VERSION 5.4 ;
NAMESCASESENSITIVE ON ;
BUSBITCHARS "[]" ;
DIVIDERCHAR "/" ;
UNITS
  DATABASE MICRONS 2000 ;
END UNITS
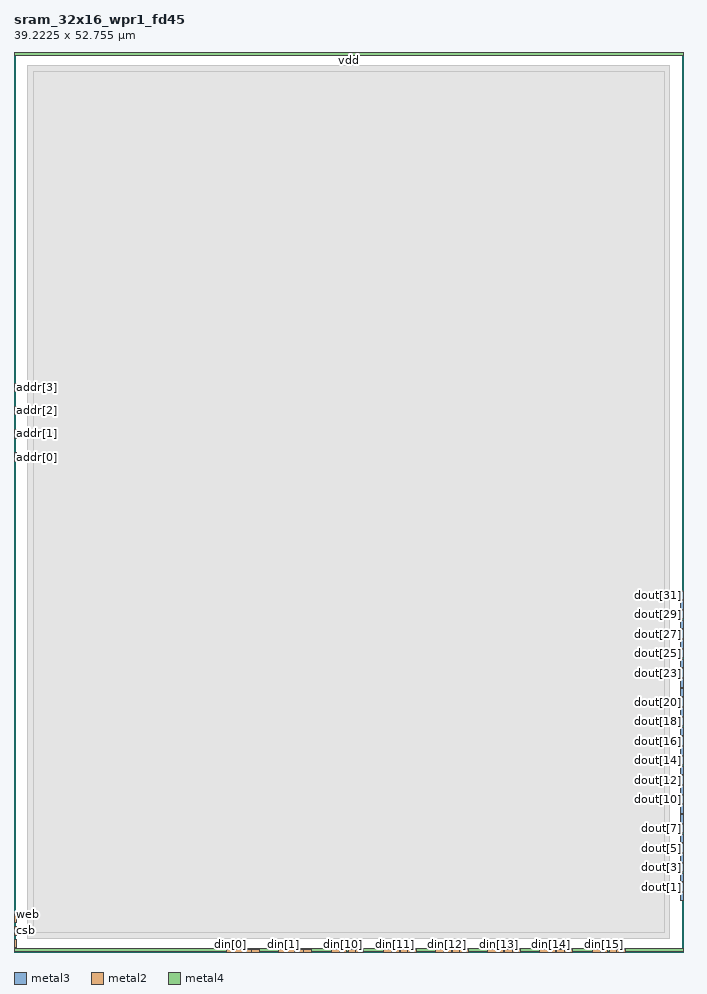
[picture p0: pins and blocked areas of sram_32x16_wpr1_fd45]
MACRO sram_32x16_wpr1_fd45
   CLASS BLOCK ;
   SIZE 39.2225 BY 52.7550 ;
   SYMMETRY X Y R90 ;
   PIN addr[0]
      DIRECTION INPUT ;
      PORT
         LAYER metal3 ;
         RECT 0.0000 28.7575 0.1600 29.2575 ;
      END
   END addr[0]
   PIN addr[1]
      DIRECTION INPUT ;
      PORT
         LAYER metal3 ;
         RECT 0.0000 30.1225 0.1600 30.6225 ;
      END
   END addr[1]
   PIN addr[2]
      DIRECTION INPUT ;
      PORT
         LAYER metal3 ;
         RECT 0.0000 31.4875 0.1600 31.9875 ;
      END
   END addr[2]
   PIN addr[3]
      DIRECTION INPUT ;
      PORT
         LAYER metal3 ;
         RECT 0.0000 32.8525 0.1600 33.3525 ;
      END
   END addr[3]
   PIN clk
      DIRECTION INPUT ;
      PORT
         LAYER metal2 ;
         RECT 0.0000 0.2425 0.1600 0.7425 ;
      END
   END clk
   PIN csb
      DIRECTION INPUT ;
      PORT
         LAYER metal2 ;
         RECT 0.0000 0.9925 0.1600 1.4925 ;
      END
   END csb
   PIN din[0]
      DIRECTION INPUT ;
      PORT
         LAYER metal2 ;
         RECT 12.4650 0.0000 12.9650 0.1600 ;
      END
   END din[0]
   PIN din[10]
      DIRECTION INPUT ;
      PORT
         LAYER metal2 ;
         RECT 19.0140 0.0000 19.5140 0.1600 ;
      END
   END din[10]
   PIN din[11]
      DIRECTION INPUT ;
      PORT
         LAYER metal2 ;
         RECT 22.0740 0.0000 22.5740 0.1600 ;
      END
   END din[11]
   PIN din[12]
      DIRECTION INPUT ;
      PORT
         LAYER metal2 ;
         RECT 25.1340 0.0000 25.6340 0.1600 ;
      END
   END din[12]
   PIN din[13]
      DIRECTION INPUT ;
      PORT
         LAYER metal2 ;
         RECT 28.1940 0.0000 28.6940 0.1600 ;
      END
   END din[13]
   PIN din[14]
      DIRECTION INPUT ;
      PORT
         LAYER metal2 ;
         RECT 31.2540 0.0000 31.7540 0.1600 ;
      END
   END din[14]
   PIN din[15]
      DIRECTION INPUT ;
      PORT
         LAYER metal2 ;
         RECT 34.3140 0.0000 34.8140 0.1600 ;
      END
   END din[15]
   PIN din[16]
      DIRECTION INPUT ;
      PORT
         LAYER metal2 ;
         RECT 13.4660 0.0000 13.9660 0.1600 ;
      END
   END din[16]
   PIN din[17]
      DIRECTION INPUT ;
      PORT
         LAYER metal2 ;
         RECT 16.5260 0.0000 17.0260 0.1600 ;
      END
   END din[17]
   PIN din[18]
      DIRECTION INPUT ;
      PORT
         LAYER metal2 ;
         RECT 19.5860 0.0000 20.0860 0.1600 ;
      END
   END din[18]
   PIN din[19]
      DIRECTION INPUT ;
      PORT
         LAYER metal2 ;
         RECT 22.6460 0.0000 23.1460 0.1600 ;
      END
   END din[19]
   PIN din[1]
      DIRECTION INPUT ;
      PORT
         LAYER metal2 ;
         RECT 15.5250 0.0000 16.0250 0.1600 ;
      END
   END din[1]
   PIN din[20]
      DIRECTION INPUT ;
      PORT
         LAYER metal2 ;
         RECT 25.7060 0.0000 26.2060 0.1600 ;
      END
   END din[20]
   PIN din[21]
      DIRECTION INPUT ;
      PORT
         LAYER metal2 ;
         RECT 28.7660 0.0000 29.2660 0.1600 ;
      END
   END din[21]
   PIN din[22]
      DIRECTION INPUT ;
      PORT
         LAYER metal2 ;
         RECT 31.8260 0.0000 32.3260 0.1600 ;
      END
   END din[22]
   PIN din[23]
      DIRECTION INPUT ;
      PORT
         LAYER metal2 ;
         RECT 34.8860 0.0000 35.3860 0.1600 ;
      END
   END din[23]
   PIN din[24]
      DIRECTION INPUT ;
      PORT
         LAYER metal2 ;
         RECT 13.8950 0.0000 14.3950 0.1600 ;
      END
   END din[24]
   PIN din[25]
      DIRECTION INPUT ;
      PORT
         LAYER metal2 ;
         RECT 16.9550 0.0000 17.4550 0.1600 ;
      END
   END din[25]
   PIN din[26]
      DIRECTION INPUT ;
      PORT
         LAYER metal2 ;
         RECT 20.0150 0.0000 20.5150 0.1600 ;
      END
   END din[26]
   PIN din[27]
      DIRECTION INPUT ;
      PORT
         LAYER metal2 ;
         RECT 23.0750 0.0000 23.5750 0.1600 ;
      END
   END din[27]
   PIN din[28]
      DIRECTION INPUT ;
      PORT
         LAYER metal2 ;
         RECT 26.1350 0.0000 26.6350 0.1600 ;
      END
   END din[28]
   PIN din[29]
      DIRECTION INPUT ;
      PORT
         LAYER metal2 ;
         RECT 29.1950 0.0000 29.6950 0.1600 ;
      END
   END din[29]
   PIN din[2]
      DIRECTION INPUT ;
      PORT
         LAYER metal2 ;
         RECT 18.5850 0.0000 19.0850 0.1600 ;
      END
   END din[2]
   PIN din[30]
      DIRECTION INPUT ;
      PORT
         LAYER metal2 ;
         RECT 32.2550 0.0000 32.7550 0.1600 ;
      END
   END din[30]
   PIN din[31]
      DIRECTION INPUT ;
      PORT
         LAYER metal2 ;
         RECT 35.3150 0.0000 35.8150 0.1600 ;
      END
   END din[31]
   PIN din[3]
      DIRECTION INPUT ;
      PORT
         LAYER metal2 ;
         RECT 21.6450 0.0000 22.1450 0.1600 ;
      END
   END din[3]
   PIN din[4]
      DIRECTION INPUT ;
      PORT
         LAYER metal2 ;
         RECT 24.7050 0.0000 25.2050 0.1600 ;
      END
   END din[4]
   PIN din[5]
      DIRECTION INPUT ;
      PORT
         LAYER metal2 ;
         RECT 27.7650 0.0000 28.2650 0.1600 ;
      END
   END din[5]
   PIN din[6]
      DIRECTION INPUT ;
      PORT
         LAYER metal2 ;
         RECT 30.8250 0.0000 31.3250 0.1600 ;
      END
   END din[6]
   PIN din[7]
      DIRECTION INPUT ;
      PORT
         LAYER metal2 ;
         RECT 33.8850 0.0000 34.3850 0.1600 ;
      END
   END din[7]
   PIN din[8]
      DIRECTION INPUT ;
      PORT
         LAYER metal2 ;
         RECT 12.8940 0.0000 13.3940 0.1600 ;
      END
   END din[8]
   PIN din[9]
      DIRECTION INPUT ;
      PORT
         LAYER metal2 ;
         RECT 15.9540 0.0000 16.4540 0.1600 ;
      END
   END din[9]
   PIN dout[0]
      DIRECTION OUTPUT ;
      PORT
         LAYER metal3 ;
         RECT 39.0625 2.9900 39.2225 3.4900 ;
      END
   END dout[0]
   PIN dout[10]
      DIRECTION OUTPUT ;
      PORT
         LAYER metal3 ;
         RECT 39.0625 8.6900 39.2225 9.1900 ;
      END
   END dout[10]
   PIN dout[11]
      DIRECTION OUTPUT ;
      PORT
         LAYER metal3 ;
         RECT 39.0625 9.2600 39.2225 9.7600 ;
      END
   END dout[11]
   PIN dout[12]
      DIRECTION OUTPUT ;
      PORT
         LAYER metal3 ;
         RECT 39.0625 9.8300 39.2225 10.3300 ;
      END
   END dout[12]
   PIN dout[13]
      DIRECTION OUTPUT ;
      PORT
         LAYER metal3 ;
         RECT 39.0625 10.4000 39.2225 10.9000 ;
      END
   END dout[13]
   PIN dout[14]
      DIRECTION OUTPUT ;
      PORT
         LAYER metal3 ;
         RECT 39.0625 10.9700 39.2225 11.4700 ;
      END
   END dout[14]
   PIN dout[15]
      DIRECTION OUTPUT ;
      PORT
         LAYER metal3 ;
         RECT 39.0625 11.5400 39.2225 12.0400 ;
      END
   END dout[15]
   PIN dout[16]
      DIRECTION OUTPUT ;
      PORT
         LAYER metal3 ;
         RECT 39.0625 12.1100 39.2225 12.6100 ;
      END
   END dout[16]
   PIN dout[17]
      DIRECTION OUTPUT ;
      PORT
         LAYER metal3 ;
         RECT 39.0625 12.6800 39.2225 13.1800 ;
      END
   END dout[17]
   PIN dout[18]
      DIRECTION OUTPUT ;
      PORT
         LAYER metal3 ;
         RECT 39.0625 13.2500 39.2225 13.7500 ;
      END
   END dout[18]
   PIN dout[19]
      DIRECTION OUTPUT ;
      PORT
         LAYER metal3 ;
         RECT 39.0625 13.8200 39.2225 14.3200 ;
      END
   END dout[19]
   PIN dout[1]
      DIRECTION OUTPUT ;
      PORT
         LAYER metal3 ;
         RECT 39.0625 3.5600 39.2225 4.0600 ;
      END
   END dout[1]
   PIN dout[20]
      DIRECTION OUTPUT ;
      PORT
         LAYER metal3 ;
         RECT 39.0625 14.3900 39.2225 14.8900 ;
      END
   END dout[20]
   PIN dout[21]
      DIRECTION OUTPUT ;
      PORT
         LAYER metal3 ;
         RECT 39.0625 14.9600 39.2225 15.4600 ;
      END
   END dout[21]
   PIN dout[22]
      DIRECTION OUTPUT ;
      PORT
         LAYER metal3 ;
         RECT 39.0625 15.5300 39.2225 16.0300 ;
      END
   END dout[22]
   PIN dout[23]
      DIRECTION OUTPUT ;
      PORT
         LAYER metal3 ;
         RECT 39.0625 16.1000 39.2225 16.6000 ;
      END
   END dout[23]
   PIN dout[24]
      DIRECTION OUTPUT ;
      PORT
         LAYER metal3 ;
         RECT 39.0625 16.6700 39.2225 17.1700 ;
      END
   END dout[24]
   PIN dout[25]
      DIRECTION OUTPUT ;
      PORT
         LAYER metal3 ;
         RECT 39.0625 17.2400 39.2225 17.7400 ;
      END
   END dout[25]
   PIN dout[26]
      DIRECTION OUTPUT ;
      PORT
         LAYER metal3 ;
         RECT 39.0625 17.8100 39.2225 18.3100 ;
      END
   END dout[26]
   PIN dout[27]
      DIRECTION OUTPUT ;
      PORT
         LAYER metal3 ;
         RECT 39.0625 18.3800 39.2225 18.8800 ;
      END
   END dout[27]
   PIN dout[28]
      DIRECTION OUTPUT ;
      PORT
         LAYER metal3 ;
         RECT 39.0625 18.9500 39.2225 19.4500 ;
      END
   END dout[28]
   PIN dout[29]
      DIRECTION OUTPUT ;
      PORT
         LAYER metal3 ;
         RECT 39.0625 19.5200 39.2225 20.0200 ;
      END
   END dout[29]
   PIN dout[2]
      DIRECTION OUTPUT ;
      PORT
         LAYER metal3 ;
         RECT 39.0625 4.1300 39.2225 4.6300 ;
      END
   END dout[2]
   PIN dout[30]
      DIRECTION OUTPUT ;
      PORT
         LAYER metal3 ;
         RECT 39.0625 20.0900 39.2225 20.5900 ;
      END
   END dout[30]
   PIN dout[31]
      DIRECTION OUTPUT ;
      PORT
         LAYER metal3 ;
         RECT 39.0625 20.6600 39.2225 21.1600 ;
      END
   END dout[31]
   PIN dout[3]
      DIRECTION OUTPUT ;
      PORT
         LAYER metal3 ;
         RECT 39.0625 4.7000 39.2225 5.2000 ;
      END
   END dout[3]
   PIN dout[4]
      DIRECTION OUTPUT ;
      PORT
         LAYER metal3 ;
         RECT 39.0625 5.2700 39.2225 5.7700 ;
      END
   END dout[4]
   PIN dout[5]
      DIRECTION OUTPUT ;
      PORT
         LAYER metal3 ;
         RECT 39.0625 5.8400 39.2225 6.3400 ;
      END
   END dout[5]
   PIN dout[6]
      DIRECTION OUTPUT ;
      PORT
         LAYER metal3 ;
         RECT 39.0625 6.4100 39.2225 6.9100 ;
      END
   END dout[6]
   PIN dout[7]
      DIRECTION OUTPUT ;
      PORT
         LAYER metal3 ;
         RECT 39.0625 6.9800 39.2225 7.4800 ;
      END
   END dout[7]
   PIN dout[8]
      DIRECTION OUTPUT ;
      PORT
         LAYER metal3 ;
         RECT 39.0625 7.5500 39.2225 8.0500 ;
      END
   END dout[8]
   PIN dout[9]
      DIRECTION OUTPUT ;
      PORT
         LAYER metal3 ;
         RECT 39.0625 8.1200 39.2225 8.6200 ;
      END
   END dout[9]
   PIN gnd
      DIRECTION INOUT ;
      USE GROUND ;
      SHAPE ABUTMENT ;
      PORT
         LAYER metal4 ;
         RECT 0.0000 0.0500 39.2225 0.2000 ;
      END
   END gnd
   PIN vdd
      DIRECTION INOUT ;
      USE POWER ;
      SHAPE ABUTMENT ;
      PORT
         LAYER metal4 ;
         RECT 0.0000 52.5550 39.2225 52.7050 ;
      END
   END vdd
   PIN web
      DIRECTION INPUT ;
      PORT
         LAYER metal2 ;
         RECT 0.0000 1.7425 0.1600 2.2425 ;
      END
   END web
   OBS
      LAYER metal1 ;
         RECT 0.8000 0.8000 38.4225 51.9550 ;
      LAYER metal2 ;
         RECT 0.8000 0.8000 38.4225 51.9550 ;
      LAYER metal3 ;
         RECT 0.8000 0.8000 38.4225 51.9550 ;
      LAYER metal4 ;
         RECT 1.1200 1.1200 38.1025 51.6350 ;
   END
END sram_32x16_wpr1_fd45
END LIBRARY
